One B-rep face of a CAD part: STEP entity #872.
In plain terms, the planar face has unit normal (-1, 0, 0).
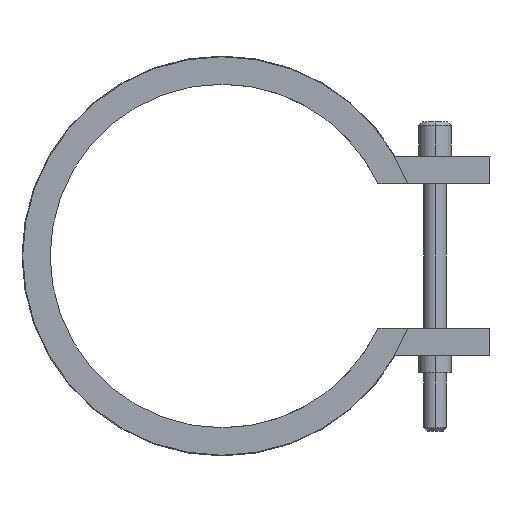
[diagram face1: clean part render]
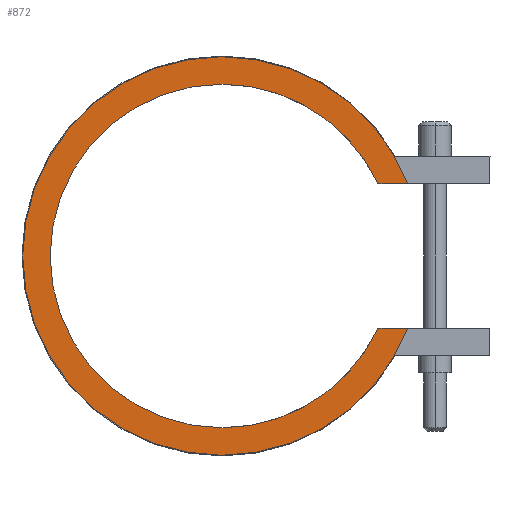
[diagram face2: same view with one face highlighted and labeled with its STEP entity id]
Its self-contained STEP definition (entity closure, numbers rounded to 3 decimals):
#410=CARTESIAN_POINT('Vertex',(-15.,-22.688,-10.5)) ;
#413=CARTESIAN_POINT('Line Origine',(-15.,-24.86,-10.5)) ;
#417=CARTESIAN_POINT('Vertex',(-15.,-27.032,-10.5)) ;
#463=CARTESIAN_POINT('Vertex',(-15.,0.,-29.)) ;
#466=CARTESIAN_POINT('Axis2P3D Location',(-15.,0.,0.)) ;
#487=CARTESIAN_POINT('Vertex',(-15.,0.,29.)) ;
#490=CARTESIAN_POINT('Axis2P3D Location',(-15.,0.,0.)) ;
#502=CARTESIAN_POINT('Axis2P3D Location',(-15.,0.,0.)) ;
#506=CARTESIAN_POINT('Vertex',(-15.,-27.032,10.5)) ;
#526=CARTESIAN_POINT('Line Origine',(-15.,-24.86,10.5)) ;
#530=CARTESIAN_POINT('Vertex',(-15.,-22.688,10.5)) ;
#818=CARTESIAN_POINT('Axis2P3D Location',(-15.,0.,0.)) ;
#822=CARTESIAN_POINT('Vertex',(-15.,0.,-25.)) ;
#845=CARTESIAN_POINT('Axis2P3D Location',(-15.,0.,0.)) ;
#850=CARTESIAN_POINT('Axis2P3D Location',(-15.,0.,0.)) ;
#854=CARTESIAN_POINT('Vertex',(-15.,0.,25.)) ;
#857=CARTESIAN_POINT('Axis2P3D Location',(-15.,0.,0.)) ;
#414=DIRECTION('Vector Direction',(0.,1.,0.)) ;
#467=DIRECTION('Axis2P3D Direction',(1.,0.,-0.)) ;
#491=DIRECTION('Axis2P3D Direction',(1.,0.,-0.)) ;
#503=DIRECTION('Axis2P3D Direction',(1.,0.,-0.)) ;
#527=DIRECTION('Vector Direction',(0.,-1.,0.)) ;
#819=DIRECTION('Axis2P3D Direction',(1.,0.,-0.)) ;
#846=DIRECTION('Axis2P3D Direction',(1.,0.,0.)) ;
#847=DIRECTION('Axis2P3D XDirection',(0.,0.,-1.)) ;
#851=DIRECTION('Axis2P3D Direction',(1.,0.,0.)) ;
#858=DIRECTION('Axis2P3D Direction',(1.,0.,0.)) ;
#468=AXIS2_PLACEMENT_3D('Circle Axis2P3D',#466,#467,$) ;
#492=AXIS2_PLACEMENT_3D('Circle Axis2P3D',#490,#491,$) ;
#504=AXIS2_PLACEMENT_3D('Circle Axis2P3D',#502,#503,$) ;
#820=AXIS2_PLACEMENT_3D('Circle Axis2P3D',#818,#819,$) ;
#848=AXIS2_PLACEMENT_3D('Plane Axis2P3D',#845,#846,#847) ;
#852=AXIS2_PLACEMENT_3D('Circle Axis2P3D',#850,#851,$) ;
#859=AXIS2_PLACEMENT_3D('Circle Axis2P3D',#857,#858,$) ;
#863=ORIENTED_EDGE('',*,*,#419,.T.) ;
#864=ORIENTED_EDGE('',*,*,#824,.T.) ;
#865=ORIENTED_EDGE('',*,*,#856,.T.) ;
#866=ORIENTED_EDGE('',*,*,#861,.T.) ;
#867=ORIENTED_EDGE('',*,*,#532,.T.) ;
#868=ORIENTED_EDGE('',*,*,#508,.F.) ;
#869=ORIENTED_EDGE('',*,*,#494,.F.) ;
#870=ORIENTED_EDGE('',*,*,#470,.F.) ;
#415=VECTOR('Line Direction',#414,1.) ;
#528=VECTOR('Line Direction',#527,1.) ;
#872=ADVANCED_FACE('14050030',(#871),#849,.F.) ;
#469=CIRCLE('generated circle',#468,29.) ;
#493=CIRCLE('generated circle',#492,29.) ;
#505=CIRCLE('generated circle',#504,29.) ;
#821=CIRCLE('generated circle',#820,25.) ;
#853=CIRCLE('generated circle',#852,25.) ;
#860=CIRCLE('generated circle',#859,25.) ;
#419=EDGE_CURVE('',#418,#411,#416,.T.) ;
#470=EDGE_CURVE('',#418,#464,#469,.T.) ;
#494=EDGE_CURVE('',#464,#488,#493,.T.) ;
#508=EDGE_CURVE('',#488,#507,#505,.T.) ;
#532=EDGE_CURVE('',#531,#507,#529,.T.) ;
#824=EDGE_CURVE('',#411,#823,#821,.T.) ;
#856=EDGE_CURVE('',#823,#855,#853,.T.) ;
#861=EDGE_CURVE('',#855,#531,#860,.T.) ;
#862=EDGE_LOOP('',(#863,#864,#865,#866,#867,#868,#869,#870)) ;
#871=FACE_OUTER_BOUND('',#862,.T.) ;
#416=LINE('Line',#413,#415) ;
#529=LINE('Line',#526,#528) ;
#849=PLANE('Plane',#848) ;
#411=VERTEX_POINT('',#410) ;
#418=VERTEX_POINT('',#417) ;
#464=VERTEX_POINT('',#463) ;
#488=VERTEX_POINT('',#487) ;
#507=VERTEX_POINT('',#506) ;
#531=VERTEX_POINT('',#530) ;
#823=VERTEX_POINT('',#822) ;
#855=VERTEX_POINT('',#854) ;
